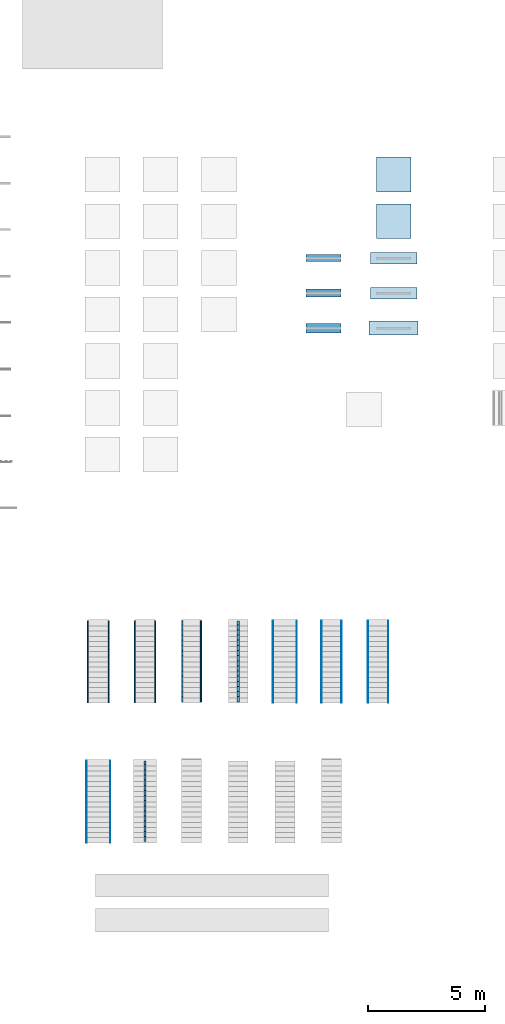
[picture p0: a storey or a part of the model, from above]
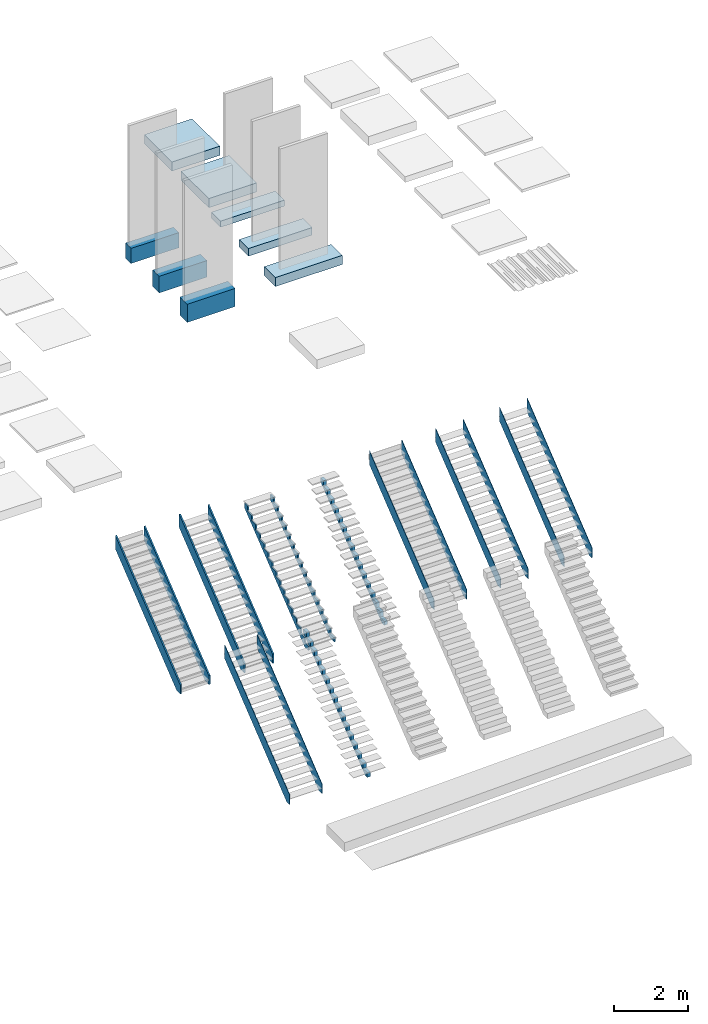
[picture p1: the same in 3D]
Properties of the parts of a building model (IFC2X3), part 3 of 3

# IfcWallStandardCase: Basic Wall:21_WA_hout-wrc-hor_rachel_tengel_iso-sw_180_20-30-10-120, Basic Wall:21_WA_hout-wrc-hor_rachel_tengel_iso-sw_180_20-30-10-120:37447
Type - Analytical Properties - Absorptance: 0.1; Heat Transfer Coefficient (U): 0.274174; Roughness: 1; Thermal mass: 47139.2; Thermal Resistance (R): 3.64732
Type - Construction - Function: Exterior; Width: 180 mm; Wrapping at Inserts: Exterior
Type - Fire Protection - ontvlambaar: no
Type - Graphics - Coarse Scale Fill Color: 8421504; Coarse Scale Fill Pattern: Solid fill
Type - Identity Data - Assembly Code: 2D(21.13); Description: buitenwand, horizontale houten geveldelen, 120mm isolatie steenwol; Keynote: d-21-000; Type Comments: geveldelen op regelwerk: vert 20x30mm op hor 10x30mm; Type Mark: 21-14
Type - Materials and Finishes - Structural Material: 20_isolatie_steenwol
Constraints - Base Constraint: Level: 00_begane grond; Base Extension Distance: 0 mm; Base is Attached: no; Base Offset: 0 mm; Location Line: Core Face: Interior; Related to Mass: no; Room Bounding: yes; Top Extension Distance: 0 mm; Top is Attached: no; Top Offset: 0 mm; Unconnected Height: 2000 mm
Dimensions - Area: 4 m2; Length: 2000 mm; Volume: 0.72 m3
Fire Protection - brandwerend: no
Phasing - Phase Created: Renvooi
Structural - Enable Analytical Model: no; Structural: no; Structural Usage: Non-bearing
Text - drs_wall_type: wall test; ifc_test: wall test
Pset_WallCommon - Reference: 21_WA_hout-wrc-hor_rachel_tengel_iso-sw_180_20-30-10-120; LoadBearing: no; ExtendToStructure: no; IsExternal: yes; ThermalTransmittance: 0.274174 kg/K/s3; Combustible: no; Compartmentation: no

# IfcWallStandardCase: Basic Wall:21_WA_mw-bestaand_100, Basic Wall:21_WA_mw-bestaand_100:31143
In: 00_begane grond
Type - PredefinedType: STANDARD; Material: 00_baksteen_bestaand 100 mm
Type - Analytical Properties - Absorptance: 0.1; Heat Transfer Coefficient (U): 4.1; Roughness: 1; Thermal mass: 120120; Thermal Resistance (R): 0.243902
Type - Construction - Function: Exterior; Width: 100 mm; Wrapping at Inserts: Do not wrap
Type - Fire Protection - ontvlambaar: no
Type - Graphics - Coarse Scale Fill Color: 8421504; Coarse Scale Fill Pattern: Solid fill
Type - Identity Data - Assembly Code: 2D(21.11); Description: bestaande buitenwand, halfsteens metselwerk; Keynote: d-21-001; Type Comments: waalformaat 200x100x50, 10mm voeg; Type Mark: 21-04
Constraints - Base Constraint: Level: 00_begane grond; Base Extension Distance: 0 mm; Base is Attached: no; Base Offset: 0 mm; Location Line: Core Face: Exterior; Related to Mass: no; Room Bounding: yes; Top Extension Distance: 0 mm; Top is Attached: no; Top Offset: 0 mm; Unconnected Height: 2000 mm
Dimensions - Area: 4 m2; Length: 2000 mm; Volume: 0.4 m3
Fire Protection - brandwerend: no
Phasing - Phase Created: Renvooi
Structural - Enable Analytical Model: no; Structural: no; Structural Usage: Non-bearing
Text - drs_wall_type: wall test; ifc_test: wall test
Pset_WallCommon - Reference: 21_WA_mw-bestaand_100; LoadBearing: no; ExtendToStructure: no; IsExternal: yes; ThermalTransmittance: 4.1 kg/K/s3; Combustible: no; Compartmentation: no

# IfcWallStandardCase: Basic Wall:21_WA_mw-bestaand_spouw_mw-bestaand_300_100-100-100, Basic Wall:21_WA_mw-bestaand_spouw_mw-bestaand_300_100-100-100:31145
In: 00_begane grond
Type - PredefinedType: STANDARD; Material: 00_baksteen_bestaand 100 mm, 00_lucht_spouw_muur_geventileerd 100 mm, 00_baksteen_bestaand 100 mm
Type - Analytical Properties - Absorptance: 0.1; Heat Transfer Coefficient (U): 1.98096; Roughness: 1; Thermal mass: 240360; Thermal Resistance (R): 0.504805
Type - Construction - Function: Exterior; Width: 300 mm; Wrapping at Inserts: Both
Type - Fire Protection - ontvlambaar: no
Type - Graphics - Coarse Scale Fill Color: 8421504; Coarse Scale Fill Pattern: Solid fill
Type - Identity Data - Assembly Code: 2B(21.22); Description: bestaande buitenwand, spouwmuur, 100-100-100; Keynote: d-21-001; Type Comments: waalformaat 200x100x50, 10mm voeg; Type Mark: 21-06
Type - Materials and Finishes - Structural Material: 00_baksteen_bestaand
Constraints - Base Constraint: Level: 00_begane grond; Base Extension Distance: 0 mm; Base is Attached: no; Base Offset: 0 mm; Location Line: Core Face: Exterior; Related to Mass: no; Room Bounding: yes; Top Extension Distance: 0 mm; Top is Attached: no; Top Offset: 0 mm; Unconnected Height: 2000 mm
Dimensions - Area: 4 m2; Length: 2000 mm; Volume: 1.2 m3
Fire Protection - brandwerend: no
Phasing - Phase Created: Renvooi
Structural - Enable Analytical Model: yes; Rebar Cover - Exterior Face: Rebar Cover Settings: Rebar Cover 1; Rebar Cover - Interior Face: Rebar Cover Settings: Rebar Cover 1; Rebar Cover - Other Faces: Rebar Cover Settings: Rebar Cover 1; Structural: yes; Structural Usage: Bearing
Text - drs_wall_type: wall test; ifc_test: wall test
Pset_WallCommon - Reference: 21_WA_mw-bestaand_spouw_mw-bestaand_300_100-100-100; LoadBearing: yes; ExtendToStructure: no; IsExternal: yes; ThermalTransmittance: 1.98096 kg/K/s3; Combustible: no; Compartmentation: no

# IfcWallStandardCase: Basic Wall:21_WA_mw_100, Basic Wall:21_WA_mw_100:30883
In: 00_begane grond
Type - PredefinedType: STANDARD; Material: 20_baksteen_wf_210x100x50_10mm_voeg_halfsteens_rood_genuanceerd 100 mm
Type - Analytical Properties - Absorptance: 0.1; Heat Transfer Coefficient (U): 4.1; Roughness: 1; Thermal mass: 120120; Thermal Resistance (R): 0.243902
Type - Construction - Function: Exterior; Width: 100 mm; Wrapping at Inserts: Do not wrap
Type - Fire Protection - ontvlambaar: no
Type - Graphics - Coarse Scale Fill Color: 8421504; Coarse Scale Fill Pattern: Solid fill
Type - Identity Data - Assembly Code: 2D(21.11); Description: buitenwand, halfsteens metselwerk; Keynote: d-21-001; Type Comments: waalformaat 200x100x50, 10mm voeg; Type Mark: 21-07
Constraints - Base Constraint: Level: 00_begane grond; Base Extension Distance: 0 mm; Base is Attached: no; Base Offset: 0 mm; Location Line: Core Face: Exterior; Related to Mass: no; Room Bounding: yes; Top Extension Distance: 0 mm; Top is Attached: no; Top Offset: 0 mm; Unconnected Height: 2000 mm
Dimensions - Area: 4 m2; Length: 2000 mm; Volume: 0.4 m3
Fire Protection - brandwerend: no
Phasing - Phase Created: Renvooi
Structural - Enable Analytical Model: no; Structural: no; Structural Usage: Non-bearing
Text - drs_wall_type: wall test; ifc_test: wall test
Pset_WallCommon - Reference: 21_WA_mw_100; LoadBearing: no; ExtendToStructure: no; IsExternal: yes; ThermalTransmittance: 4.1 kg/K/s3; Combustible: no; Compartmentation: no

# IfcWallStandardCase: Basic Wall:21_WA_mw_210, Basic Wall:21_WA_mw_210:30884
In: 00_begane grond
Type - PredefinedType: STANDARD; Material: 20_baksteen_wf_210x100x50_10mm_voeg_halfsteens_rood_genuanceerd 210 mm
Type - Analytical Properties - Absorptance: 0.1; Heat Transfer Coefficient (U): 1.95238; Roughness: 1; Thermal mass: 252252; Thermal Resistance (R): 0.512195
Type - Construction - Function: Exterior; Width: 210 mm; Wrapping at Inserts: Do not wrap
Type - Fire Protection - ontvlambaar: no
Type - Graphics - Coarse Scale Fill Color: 8421504; Coarse Scale Fill Pattern: Solid fill
Type - Identity Data - Assembly Code: 2B(21.21); Description: buitenwand, steens metselwerk; Keynote: d-21-001; Type Comments: waalformaat 200x100x50, 10mm voeg; Type Mark: 21-08
Type - Materials and Finishes - Structural Material: 20_baksteen_wf_210x100x50_10mm_voeg_halfsteens_rood_genuanceerd
Constraints - Base Constraint: Level: 00_begane grond; Base Extension Distance: 0 mm; Base is Attached: no; Base Offset: 0 mm; Location Line: Core Face: Exterior; Related to Mass: no; Room Bounding: yes; Top Extension Distance: 0 mm; Top is Attached: no; Top Offset: 0 mm; Unconnected Height: 2000 mm
Dimensions - Area: 4 m2; Length: 2000 mm; Volume: 0.84 m3
Fire Protection - brandwerend: no
Phasing - Phase Created: Renvooi
Structural - Enable Analytical Model: yes; Rebar Cover - Exterior Face: Rebar Cover Settings: Rebar Cover 1; Rebar Cover - Interior Face: Rebar Cover Settings: Rebar Cover 1; Rebar Cover - Other Faces: Rebar Cover Settings: Rebar Cover 1; Structural: yes; Structural Usage: Bearing
Text - drs_wall_type: wall test; ifc_test: wall test
Pset_WallCommon - Reference: 21_WA_mw_210; LoadBearing: yes; ExtendToStructure: no; IsExternal: yes; ThermalTransmittance: 1.95238 kg/K/s3; Combustible: no; Compartmentation: no

# IfcWallStandardCase: Basic Wall:21_WA_mw_bestaand_210, Basic Wall:21_WA_mw_bestaand_210:31144
In: 00_begane grond
Type - PredefinedType: STANDARD; Material: 00_baksteen_bestaand 210 mm
Type - Analytical Properties - Absorptance: 0.1; Heat Transfer Coefficient (U): 1.95238; Roughness: 1; Thermal mass: 252252; Thermal Resistance (R): 0.512195
Type - Construction - Function: Exterior; Width: 210 mm; Wrapping at Inserts: Do not wrap
Type - Fire Protection - ontvlambaar: no
Type - Graphics - Coarse Scale Fill Color: 8421504; Coarse Scale Fill Pattern: Solid fill
Type - Identity Data - Assembly Code: 2B(21.21); Description: bestaande buitenwand, steens metselwerk; Keynote: d-21-001; Type Comments: waalformaat 200x100x50, 10mm voeg; Type Mark: 21-05
Type - Materials and Finishes - Structural Material: 00_baksteen_bestaand
Constraints - Base Constraint: Level: 00_begane grond; Base Extension Distance: 0 mm; Base is Attached: no; Base Offset: 0 mm; Location Line: Core Face: Exterior; Related to Mass: no; Room Bounding: yes; Top Extension Distance: 0 mm; Top is Attached: no; Top Offset: 0 mm; Unconnected Height: 2000 mm
Dimensions - Area: 4 m2; Length: 2000 mm; Volume: 0.84 m3
Fire Protection - brandwerend: no
Phasing - Phase Created: Renvooi
Structural - Enable Analytical Model: yes; Rebar Cover - Exterior Face: Rebar Cover Settings: Rebar Cover 1; Rebar Cover - Interior Face: Rebar Cover Settings: Rebar Cover 1; Rebar Cover - Other Faces: Rebar Cover Settings: Rebar Cover 1; Structural: yes; Structural Usage: Bearing
Text - drs_wall_type: wall test; ifc_test: wall test
Pset_WallCommon - Reference: 21_WA_mw_bestaand_210; LoadBearing: yes; ExtendToStructure: no; IsExternal: yes; ThermalTransmittance: 1.95238 kg/K/s3; Combustible: no; Compartmentation: no

# IfcWallStandardCase: Basic Wall:21_WA_mw_spouw_170_100-70, Basic Wall:21_WA_mw_spouw_170_100-70:35351
In: 00_begane grond
Type - PredefinedType: STANDARD; Material: 20_baksteen_wf_210x100x50_10mm_voeg_halfsteens_rood_genuanceerd 100 mm, 00_lucht_spouw_muur_geventileerd 70 mm
Type - Analytical Properties - Absorptance: 0.1; Heat Transfer Coefficient (U): 3.90927; Roughness: 1; Thermal mass: 120204; Thermal Resistance (R): 0.255802
Type - Construction - Function: Exterior; Width: 170 mm; Wrapping at Inserts: Do not wrap
Type - Fire Protection - ontvlambaar: no
Type - Graphics - Coarse Scale Fill Color: 8421504; Coarse Scale Fill Pattern: Solid fill
Type - Identity Data - Assembly Code: 2D(21.12); Description: buitenwand, spouwmuur: 100mm mw, 70mm luchtspouw; Keynote: d-21-001; Type Comments: waalformaat 200x100x50, 10mm voeg; Type Mark: 21-10
Constraints - Base Constraint: Level: 00_begane grond; Base Extension Distance: 0 mm; Base is Attached: no; Base Offset: 0 mm; Location Line: Core Face: Interior; Related to Mass: no; Room Bounding: yes; Top Extension Distance: 0 mm; Top is Attached: no; Top Offset: 0 mm; Unconnected Height: 2000 mm
Dimensions - Area: 4 m2; Length: 2000 mm; Volume: 0.68 m3
Fire Protection - brandwerend: no
Phasing - Phase Created: Renvooi
Structural - Enable Analytical Model: no; Structural: no; Structural Usage: Non-bearing
Text - drs_wall_type: wall test; ifc_test: wall test
Pset_WallCommon - Reference: 21_WA_mw_spouw_170_100-70; LoadBearing: no; ExtendToStructure: no; IsExternal: yes; ThermalTransmittance: 3.90927 kg/K/s3; Combustible: no; Compartmentation: no

# IfcWallStandardCase: Basic Wall:21_WA_mw_spouw_iso-sw_170_100-20-50, Basic Wall:21_WA_mw_spouw_iso-sw_170_100-20-50:35352
In: 00_begane grond
Type - PredefinedType: STANDARD; Material: 20_baksteen_wf_210x100x50_10mm_voeg_halfsteens_rood_genuanceerd 100 mm, 00_lucht_spouw_muur_geventileerd 20 mm, 20_isolatie_steenwol 50 mm
Type - Analytical Properties - Absorptance: 0.1; Heat Transfer Coefficient (U): 0.582109; Roughness: 1; Thermal mass: 127244; Thermal Resistance (R): 1.71789
Type - Construction - Function: Exterior; Width: 170 mm; Wrapping at Inserts: Exterior
Type - Fire Protection - ontvlambaar: no
Type - Graphics - Coarse Scale Fill Color: 8421504; Coarse Scale Fill Pattern: Solid fill
Type - Identity Data - Assembly Code: 2D(21.12); Description: buitenwand, spouwmuur: 100mm mw, 20mm luchtspouw, 50mm isolatie steenwol; Keynote: d-21-001; Type Comments: waalformaat 200x100x50, 10mm voeg; Type Mark: 21-11
Constraints - Base Constraint: Level: 00_begane grond; Base Extension Distance: 0 mm; Base is Attached: no; Base Offset: 0 mm; Location Line: Core Face: Interior; Related to Mass: no; Room Bounding: yes; Top Extension Distance: 0 mm; Top is Attached: no; Top Offset: 0 mm; Unconnected Height: 2000 mm
Dimensions - Area: 4 m2; Length: 2000 mm; Volume: 0.68 m3
Fire Protection - brandwerend: no
Phasing - Phase Created: Renvooi
Structural - Enable Analytical Model: no; Structural: no; Structural Usage: Non-bearing
Text - drs_wall_type: wall test; ifc_test: wall test
Pset_WallCommon - Reference: 21_WA_mw_spouw_iso-sw_170_100-20-50; LoadBearing: no; ExtendToStructure: no; IsExternal: yes; ThermalTransmittance: 0.582109 kg/K/s3; Combustible: no; Compartmentation: no

# IfcWallStandardCase: Basic Wall:21_WA_mw_spouw_iso-sw_200_100-30-70 (2)
In: 00_begane grond
Type - PredefinedType: STANDARD; Material: 20_baksteen_wf_210x100x50_10mm_voeg_halfsteens_rood_genuanceerd 100 mm, 00_lucht_spouw_muur_geventileerd 30 mm, 20_isolatie_steenwol 70 mm
Type - Analytical Properties - Absorptance: 0.1; Heat Transfer Coefficient (U): 0.433308; Roughness: 1; Thermal mass: 130096; Thermal Resistance (R): 2.30783
Type - Construction - Function: Exterior; Width: 200 mm; Wrapping at Inserts: Exterior
Type - Fire Protection - ontvlambaar: no
Type - Graphics - Coarse Scale Fill Color: 8421504; Coarse Scale Fill Pattern: Solid fill
Type - Identity Data - Assembly Code: 2D(21.12); Description: buitenwand, spouwmuur: 100mm mw, 30mm luchtspouw, 70mm isolatie steenwol; Keynote: d-21-001; Type Comments: waalformaat 200x100x50, 10mm voeg; Type Mark: 21-12
Constraints - Base Constraint: Level: 00_begane grond; Base Extension Distance: 0 mm; Base is Attached: no; Base Offset: 0 mm; Location Line: Core Face: Interior; Related to Mass: no; Room Bounding: yes; Top Extension Distance: 0 mm; Top is Attached: no; Top Offset: 0 mm; Unconnected Height: 2000 mm
Dimensions - Area: 4 m2; Length: 2000 mm; Volume: 0.8 m3
Fire Protection - brandwerend: no
Phasing - Phase Created: Renvooi
Structural - Enable Analytical Model: no; Structural: no; Structural Usage: Non-bearing
Text - drs_wall_type: wall test; ifc_test: wall test
Pset_WallCommon - Reference: 21_WA_mw_spouw_iso-sw_200_100-30-70; LoadBearing: no; ExtendToStructure: no; IsExternal: yes; ThermalTransmittance: 0.433308 kg/K/s3; Combustible: no; Compartmentation: no
Name (Basic Wall:21_WA_mw_spouw_iso-sw_200_100-30-70:...)
35353
35357

# IfcWallStandardCase: Basic Wall:21_WA_mw_spouw_mw_300_100-100-100, Basic Wall:21_WA_mw_spouw_mw_300_100-100-100:30885
In: 00_begane grond
Type - PredefinedType: STANDARD; Material: 20_baksteen_wf_210x100x50_10mm_voeg_halfsteens_rood_genuanceerd 100 mm, 00_lucht_spouw_muur_geventileerd 100 mm, 20_baksteen_wf_210x100x50_10mm_voeg_halfsteens_rood_genuanceerd 100 mm
Type - Analytical Properties - Absorptance: 0.1; Heat Transfer Coefficient (U): 1.98096; Roughness: 1; Thermal mass: 240360; Thermal Resistance (R): 0.504805
Type - Construction - Function: Exterior; Width: 300 mm; Wrapping at Inserts: Both
Type - Fire Protection - ontvlambaar: no
Type - Graphics - Coarse Scale Fill Color: 8421504; Coarse Scale Fill Pattern: Solid fill
Type - Identity Data - Assembly Code: 2B(21.22); Description: buitenwand, spouwmuur, 100-100-100; Keynote: d-21-001; Type Comments: waalformaat 200x100x50, 10mm voeg; Type Mark: 21-09
Type - Materials and Finishes - Structural Material: 20_baksteen_wf_210x100x50_10mm_voeg_halfsteens_rood_genuanceerd
Constraints - Base Constraint: Level: 00_begane grond; Base Extension Distance: 0 mm; Base is Attached: no; Base Offset: 0 mm; Location Line: Core Face: Exterior; Related to Mass: no; Room Bounding: yes; Top Extension Distance: 0 mm; Top is Attached: no; Top Offset: 0 mm; Unconnected Height: 2000 mm
Dimensions - Area: 4 m2; Length: 2000 mm; Volume: 1.2 m3
Fire Protection - brandwerend: no
Phasing - Phase Created: Renvooi
Structural - Enable Analytical Model: yes; Rebar Cover - Exterior Face: Rebar Cover Settings: Rebar Cover 1; Rebar Cover - Interior Face: Rebar Cover Settings: Rebar Cover 1; Rebar Cover - Other Faces: Rebar Cover Settings: Rebar Cover 1; Structural: yes; Structural Usage: Bearing
Text - drs_wall_type: wall test; ifc_test: wall test
Pset_WallCommon - Reference: 21_WA_mw_spouw_mw_300_100-100-100; LoadBearing: yes; ExtendToStructure: no; IsExternal: yes; ThermalTransmittance: 1.98096 kg/K/s3; Combustible: no; Compartmentation: no

# IfcWallStandardCase: Basic Wall:21_WA_sandwichpaneel_100x1000, Basic Wall:21_WA_sandwichpaneel_100x1000:50449
In: 00_begane grond
Type - PredefinedType: STANDARD; Material: 41_staal_geanodizeerd_wit 1.6 mm, 20_isolatie_PIR 96.8 mm, 41_staal_geanodizeerd_wit 1.6 mm
Type - Analytical Properties - Absorptance: 0.1; Heat Transfer Coefficient (U): 0.309911; Roughness: 1; Thermal mass: 18460.9; Thermal Resistance (R): 3.22674
Type - Construction - Function: Exterior; Width: 100 mm; Wrapping at Inserts: Exterior
Type - Fire Protection - ontvlambaar: no
Type - Graphics - Coarse Scale Fill Color: 8421504; Coarse Scale Fill Pattern: Solid fill
Type - Identity Data - Assembly Code: 2D(21.13); Description: buitenwand, sandwichpaneel 100mm, PIR isolatie; Keynote: d-21-000; Type Comments: stalen buitenplaat = 0.63mm, stalen binnenplaat = 0.50mm; Type Mark: 21-16
Constraints - Base Constraint: Level: 00_begane grond; Base Extension Distance: 0 mm; Base is Attached: no; Base Offset: 0 mm; Location Line: Core Face: Interior; Related to Mass: no; Room Bounding: yes; Top Extension Distance: 0 mm; Top is Attached: no; Top Offset: 0 mm; Unconnected Height: 2000 mm
Dimensions - Area: 4 m2; Length: 2000 mm; Volume: 0.4 m3
Fire Protection - brandwerend: no
Phasing - Phase Created: Renvooi
Structural - Enable Analytical Model: no; Structural: no; Structural Usage: Non-bearing
Text - drs_wall_type: wall test; ifc_test: wall test
Pset_WallCommon - Reference: 21_WA_sandwichpaneel_100x1000; LoadBearing: no; ExtendToStructure: no; IsExternal: yes; ThermalTransmittance: 0.309911 kg/K/s3; Combustible: no; Compartmentation: no

# IfcWallStandardCase: Basic Wall:21_WA_spouw_iso-sw_140_40-100, Basic Wall:21_WA_spouw_iso-sw_140_40-100:228435
In: 00_begane grond
Type - PredefinedType: STANDARD; Material: 00_lucht_spouw_muur_geventileerd 40 mm, 20_isolatie_steenwol 100 mm
Type - Analytical Properties - Absorptance: 0.1; Heat Transfer Coefficient (U): 0.339216; Roughness: 1; Thermal mass: 14248.2; Thermal Resistance (R): 2.94798
Type - Construction - Function: Exterior; Width: 140 mm; Wrapping at Inserts: Exterior
Type - Fire Protection - ontvlambaar: no
Type - Graphics - Coarse Scale Fill Color: 8421504; Coarse Scale Fill Pattern: Solid fill
Type - Identity Data - Assembly Code: 2E(22.12); Description: 40mm luchtspouw, 100mm isolatie steenwol; Keynote: d-21-001; Type Mark: 21-17
Constraints - Base Constraint: Level: 00_begane grond; Base Extension Distance: 0 mm; Base is Attached: no; Base Offset: 0 mm; Location Line: Core Face: Interior; Related to Mass: no; Room Bounding: yes; Top Extension Distance: 0 mm; Top is Attached: no; Top Offset: 0 mm; Unconnected Height: 2000 mm
Dimensions - Area: 4 m2; Length: 2000 mm; Volume: 0.56 m3
Fire Protection - brandwerend: no
Phasing - Phase Created: Renvooi
Structural - Enable Analytical Model: no; Structural: no; Structural Usage: Non-bearing
Text - drs_wall_type: wall test; ifc_test: wall test
Pset_WallCommon - Reference: 21_WA_spouw_iso-sw_140_40-100; LoadBearing: no; ExtendToStructure: no; IsExternal: yes; ThermalTransmittance: 0.339216 kg/K/s3; Combustible: no; Compartmentation: no

# IfcWallStandardCase: Basic Wall:21_WA_stucwerk_iso-eps_150_30-120, Basic Wall:21_WA_stucwerk_iso-eps_150_30-120:50293
In: 00_begane grond
Type - PredefinedType: STANDARD; Material: 40_stucwerk_exterieur_grof_wit 30 mm, 20_isolatie_EPS 120 mm
Type - Analytical Properties - Absorptance: 0.1; Heat Transfer Coefficient (U): 0.286747; Roughness: 1; Thermal mass: 36313.2; Thermal Resistance (R): 3.48739
Type - Construction - Function: Exterior; Width: 150 mm; Wrapping at Inserts: Exterior
Type - Fire Protection - ontvlambaar: no
Type - Graphics - Coarse Scale Fill Color: 8421504; Coarse Scale Fill Pattern: Solid fill
Type - Identity Data - Assembly Code: 2D(21.10); Description: buitenwand, 30mm stucwerk, 120mm isolatie EPS; Keynote: d-21-000; Type Mark: 21-15
Constraints - Base Constraint: Level: 00_begane grond; Base Extension Distance: 0 mm; Base is Attached: no; Base Offset: 0 mm; Location Line: Core Face: Interior; Related to Mass: no; Room Bounding: yes; Top Extension Distance: 0 mm; Top is Attached: no; Top Offset: 0 mm; Unconnected Height: 2000 mm
Dimensions - Area: 4 m2; Length: 2000 mm; Volume: 0.6 m3
Fire Protection - brandwerend: no
Phasing - Phase Created: Renvooi
Structural - Enable Analytical Model: no; Structural: no; Structural Usage: Non-bearing
Text - drs_wall_type: wall test; ifc_test: wall test
Pset_WallCommon - Reference: 21_WA_stucwerk_iso-eps_150_30-120; LoadBearing: no; ExtendToStructure: no; IsExternal: yes; ThermalTransmittance: 0.286747 kg/K/s3; Combustible: no; Compartmentation: no

# IfcWallStandardCase: Basic Wall:22_WA_cb_G2/400_100, Basic Wall:22_WA_cb_G2/400_100:53177
In: 00_begane grond
Type - PredefinedType: STANDARD; Material: 22_cellenbeton G2/400 100 mm
Type - Analytical Properties - Absorptance: 0.1; Heat Transfer Coefficient (U): 1.2; Roughness: 1; Thermal mass: 40320; Thermal Resistance (R): 0.833333
Type - Construction - Function: Interior; Width: 100 mm; Wrapping at Inserts: Do not wrap
Type - Fire Protection - ontvlambaar: no
Type - Graphics - Coarse Scale Fill Color: 8421504; Coarse Scale Fill Pattern: Solid fill
Type - Identity Data - Assembly Code: 2E(22.11); Description: niet-dragende binnenwand cellenbeton; Keynote: d-22-003; Type Comments: blokken/elementen gelijmd, d =100mm; Type Mark: 22-02
Constraints - Base Constraint: Level: 00_begane grond; Base Extension Distance: 0 mm; Base is Attached: no; Base Offset: 0 mm; Location Line: Core Face: Exterior; Related to Mass: no; Room Bounding: yes; Top Extension Distance: 0 mm; Top is Attached: no; Top Offset: 0 mm; Unconnected Height: 2000 mm
Dimensions - Area: 4 m2; Length: 2000 mm; Volume: 0.4 m3
Fire Protection - brandwerend: no
Phasing - Phase Created: Renvooi
Structural - Enable Analytical Model: no; Structural: no; Structural Usage: Non-bearing
Pset_WallCommon - Reference: 22_WA_cb_G2/400_100; LoadBearing: no; ExtendToStructure: no; IsExternal: no; ThermalTransmittance: 1.2 kg/K/s3; Combustible: no; Compartmentation: no

# IfcWallStandardCase: Basic Wall:22_WA_glazen_bouwsteen_80, Basic Wall:22_WA_glazen_bouwsteen_80:54317
In: 00_begane grond
Type - PredefinedType: STANDARD; Material: 22_glazen_bouwsteen 80 mm
Type - Analytical Properties - Absorptance: 0.1; Heat Transfer Coefficient (U): 2.81125; Roughness: 1; Thermal mass: 62832; Thermal Resistance (R): 0.355714
Type - Construction - Function: Interior; Width: 80 mm; Wrapping at Inserts: Do not wrap
Type - Fire Protection - ontvlambaar: no
Type - Graphics - Coarse Scale Fill Color: 8421504; Coarse Scale Fill Pattern: Solid fill
Type - Identity Data - Assembly Code: 2E(22.10); Description: niet-dragende binnenwand glazen bouwstenen; Keynote: d-22-000; Type Comments: blokken gemetseld, 190x190mm, voeg 10mm, d =80mm; Type Mark: 22-04
Constraints - Base Constraint: Level: 00_begane grond; Base Extension Distance: 0 mm; Base is Attached: no; Base Offset: 0 mm; Location Line: Core Face: Exterior; Related to Mass: no; Room Bounding: yes; Top Extension Distance: 0 mm; Top is Attached: no; Top Offset: 0 mm; Unconnected Height: 2000 mm
Dimensions - Area: 4 m2; Length: 2000 mm; Volume: 0.32 m3
Fire Protection - brandwerend: no
Phasing - Phase Created: Renvooi
Structural - Enable Analytical Model: no; Structural: no; Structural Usage: Non-bearing
Pset_WallCommon - Reference: 22_WA_glazen_bouwsteen_80; LoadBearing: no; ExtendToStructure: no; IsExternal: no; ThermalTransmittance: 2.81125 kg/K/s3; Combustible: no; Compartmentation: no

# IfcWallStandardCase: Basic Wall:22_WA_kzs_CS12_100, Basic Wall:22_WA_kzs_CS12_100:53048
In: 00_begane grond
Type - PredefinedType: STANDARD; Material: 22_kalkzandsteen_CS12 100 mm
Type - Analytical Properties - Absorptance: 0.1; Heat Transfer Coefficient (U): 8.6; Roughness: 1; Thermal mass: 155400; Thermal Resistance (R): 0.116279
Type - Construction - Function: Interior; Width: 100 mm; Wrapping at Inserts: Do not wrap
Type - Fire Protection - ontvlambaar: no
Type - Graphics - Coarse Scale Fill Color: 8421504; Coarse Scale Fill Pattern: Solid fill
Type - Identity Data - Assembly Code: 2E(22.11); Description: niet-dragende binnenwand kalkzandsteen, klasse CS12; Keynote: d-22-051; Type Comments: blokken/elementen gelijmd, d =100mm; Type Mark: 22-01
Constraints - Base Constraint: Level: 00_begane grond; Base Extension Distance: 0 mm; Base is Attached: no; Base Offset: 0 mm; Location Line: Core Face: Exterior; Related to Mass: no; Room Bounding: yes; Top Extension Distance: 0 mm; Top is Attached: no; Top Offset: 0 mm; Unconnected Height: 2000 mm
Dimensions - Area: 4 m2; Length: 2000 mm; Volume: 0.4 m3
Fire Protection - brandwerend: no
Phasing - Phase Created: Renvooi
Structural - Enable Analytical Model: no; Structural: no; Structural Usage: Non-bearing
Pset_WallCommon - Reference: 22_WA_kzs_CS12_100; LoadBearing: no; ExtendToStructure: no; IsExternal: no; ThermalTransmittance: 8.6 kg/K/s3; Combustible: no; Compartmentation: no

# IfcWallStandardCase: Basic Wall:22_WA_ms-wand_gips_isolatie_gips_95_12.5-70-12.5, Basic Wall:22_WA_ms-wand_gips_isolatie_gips_95_12.5-70-12.5:53216
In: 00_begane grond
Type - PredefinedType: STANDARD; Material: 22_gips_beplating_wand_610mm 12.5 mm, 20_isolatie_steenwol 70 mm, 22_gips_beplating_wand_610mm 12.5 mm
Type - Analytical Properties - Absorptance: 0.1; Heat Transfer Coefficient (U): 0.476807; Roughness: 1; Thermal mass: 33040; Thermal Resistance (R): 2.09729
Type - Construction - Function: Interior; Width: 95 mm; Wrapping at Inserts: Do not wrap
Type - Fire Protection - ontvlambaar: no
Type - Graphics - Coarse Scale Fill Color: 8421504; Coarse Scale Fill Pattern: Solid fill
Type - Identity Data - Assembly Code: 2E(22.13); Description: niet-dragende binnenwand metalstud, 70mm isolatie steenwol; Keynote: d-22-000; Type Comments: 12.5mm gipsplaat aan beide zijden; Type Mark: 22-03
Constraints - Base Constraint: Level: 00_begane grond; Base Extension Distance: 0 mm; Base is Attached: no; Base Offset: 0 mm; Location Line: Core Face: Exterior; Related to Mass: no; Room Bounding: yes; Top Extension Distance: 0 mm; Top is Attached: no; Top Offset: 0 mm; Unconnected Height: 2000 mm
Dimensions - Area: 4 m2; Length: 2000 mm; Volume: 0.38 m3
Fire Protection - brandwerend: no
Phasing - Phase Created: Renvooi
Structural - Enable Analytical Model: no; Structural: no; Structural Usage: Non-bearing
Pset_WallCommon - Reference: 22_WA_ms-wand_gips_isolatie_gips_95_12.5-70-12.5; LoadBearing: no; ExtendToStructure: no; IsExternal: no; ThermalTransmittance: 0.476807 kg/K/s3; Combustible: no; Compartmentation: no

# IfcWallStandardCase: Basic Wall:28_WA_cb_G4/600_100, Basic Wall:28_WA_cb_G4/600_100:51594
In: 00_begane grond
Type - PredefinedType: STANDARD; Material: 28_cellenbeton_G4/600 100 mm
Type - Analytical Properties - Absorptance: 0.1; Heat Transfer Coefficient (U): 1.6; Roughness: 1; Thermal mass: 48720; Thermal Resistance (R): 0.625
Type - Construction - Function: Core-shaft; Width: 100 mm; Wrapping at Inserts: Do not wrap
Type - Fire Protection - ontvlambaar: no
Type - Graphics - Coarse Scale Fill Color: 8421504; Coarse Scale Fill Pattern: Solid fill
Type - Identity Data - Assembly Code: 2B(28.21); Description: dragende binnenwand cellenbeton, klasse G4/600; Keynote: d-22-004; Type Comments: blokken/elementen gelijmd, d =100mm; Type Mark: 28-05
Type - Materials and Finishes - Structural Material: 28_cellenbeton_G4/600
Constraints - Base Constraint: Level: 00_begane grond; Base Extension Distance: 0 mm; Base is Attached: no; Base Offset: 0 mm; Location Line: Core Face: Exterior; Related to Mass: no; Room Bounding: yes; Top Extension Distance: 0 mm; Top is Attached: no; Top Offset: 0 mm; Unconnected Height: 2000 mm
Dimensions - Area: 4 m2; Length: 2000 mm; Volume: 0.4 m3
Fire Protection - brandwerend: no
Phasing - Phase Created: Renvooi
Structural - Enable Analytical Model: yes; Rebar Cover - Exterior Face: Rebar Cover Settings: Rebar Cover 1; Rebar Cover - Interior Face: Rebar Cover Settings: Rebar Cover 1; Rebar Cover - Other Faces: Rebar Cover Settings: Rebar Cover 1; Structural: yes; Structural Usage: Bearing
Text - drs_wall_type: wall test; ifc_test: wall test
Pset_WallCommon - Reference: 28_WA_cb_G4/600_100; LoadBearing: yes; ExtendToStructure: no; IsExternal: yes; ThermalTransmittance: 1.6 kg/K/s3; Combustible: no; Compartmentation: no

# IfcWallStandardCase: Basic Wall:28_WA_cb_G4/600_150, Basic Wall:28_WA_cb_G4/600_150:228787
In: 00_begane grond
Type - PredefinedType: STANDARD; Material: 28_cellenbeton_G4/600 150 mm
Type - Analytical Properties - Absorptance: 0.1; Heat Transfer Coefficient (U): 1.06667; Roughness: 1; Thermal mass: 73080; Thermal Resistance (R): 0.9375
Type - Construction - Function: Core-shaft; Width: 150 mm; Wrapping at Inserts: Do not wrap
Type - Fire Protection - ontvlambaar: no
Type - Graphics - Coarse Scale Fill Color: 8421504; Coarse Scale Fill Pattern: Solid fill
Type - Identity Data - Assembly Code: 2B(28.21); Description: dragende binnenwand cellenbeton, klasse G4/600; Keynote: d-22-004; Type Comments: blokken/elementen gelijmd, d =100mm; Type Mark: 28-06
Type - Materials and Finishes - Structural Material: 28_cellenbeton_G4/600
Constraints - Base Constraint: Level: 00_begane grond; Base Extension Distance: 0 mm; Base is Attached: no; Base Offset: 0 mm; Location Line: Core Face: Exterior; Related to Mass: no; Room Bounding: yes; Top Extension Distance: 0 mm; Top is Attached: no; Top Offset: 0 mm; Unconnected Height: 2000 mm
Dimensions - Area: 4 m2; Length: 2000 mm; Volume: 0.6 m3
Fire Protection - brandwerend: no
Phasing - Phase Created: Renvooi
Structural - Enable Analytical Model: yes; Rebar Cover - Exterior Face: Rebar Cover Settings: Rebar Cover 1; Rebar Cover - Interior Face: Rebar Cover Settings: Rebar Cover 1; Rebar Cover - Other Faces: Rebar Cover Settings: Rebar Cover 1; Structural: yes; Structural Usage: Bearing
Text - drs_wall_type: wall test; ifc_test: wall test
Pset_WallCommon - Reference: 28_WA_cb_G4/600_150; LoadBearing: yes; ExtendToStructure: no; IsExternal: yes; ThermalTransmittance: 1.06667 kg/K/s3; Combustible: no; Compartmentation: no

# IfcWallStandardCase: Basic Wall:28_WA_ihwgb_C25_150, Basic Wall:28_WA_ihwgb_C25_150:228590
In: 00_begane grond
Type - PredefinedType: STANDARD; Material: 28_beton_ihwg_C25_30 150 mm
Type - Analytical Properties - Absorptance: 0.1; Heat Transfer Coefficient (U): 6.97333; Roughness: 1; Thermal mass: 226665; Thermal Resistance (R): 0.143403
Type - Construction - Function: Core-shaft; Width: 150 mm; Wrapping at Inserts: Do not wrap
Type - Graphics - Coarse Scale Fill Color: 0
Type - Identity Data - Assembly Code: 2B(28.21); Description: dragende binnenwand beton, klasse C25; Keynote: d-22-004; Type Comments: in het werk gestort , d =150mm; Type Mark: 28-08
Type - Materials and Finishes - Structural Material: 28_beton_ihwg_C25_30
Constraints - Base Constraint: Level: 00_begane grond; Base Extension Distance: 0 mm; Base is Attached: no; Base Offset: 0 mm; Location Line: Core Face: Exterior; Related to Mass: no; Room Bounding: yes; Top Extension Distance: 0 mm; Top is Attached: no; Top Offset: 0 mm; Unconnected Height: 2000 mm
Dimensions - Area: 4 m2; Length: 2000 mm; Volume: 0.6 m3
Fire Protection - brandwerend: no
Phasing - Phase Created: Renvooi
Structural - Enable Analytical Model: yes; Rebar Cover - Exterior Face: Rebar Cover Settings: Rebar Cover 1; Rebar Cover - Interior Face: Rebar Cover Settings: Rebar Cover 1; Rebar Cover - Other Faces: Rebar Cover Settings: Rebar Cover 1; Structural: yes; Structural Usage: Bearing
Text - drs_wall_type: wall test; ifc_test: wall test
Pset_WallCommon - Reference: 28_WA_ihwgb_C25_150; LoadBearing: yes; ExtendToStructure: no; IsExternal: yes; ThermalTransmittance: 6.97333 kg/K/s3; Compartmentation: no

# IfcWallStandardCase: Basic Wall:28_WA_kzs-CS16_spouw_kzs-C16_330_150-30-150, Basic Wall:28_WA_kzs-CS16_spouw_kzs-C16_330_150-30-150:50784
In: 00_begane grond
Type - PredefinedType: STANDARD; Material: 28_kalkzandsteen_CS16 150 mm, 00_lucht_spouw_muur_geventileerd 30 mm, 28_kalkzandsteen_CS16 150 mm
Type - Analytical Properties - Absorptance: 0.1; Heat Transfer Coefficient (U): 2.82536; Roughness: 1; Thermal mass: 466236; Thermal Resistance (R): 0.353937
Type - Construction - Function: Core-shaft; Width: 330 mm; Wrapping at Inserts: Do not wrap
Type - Fire Protection - ontvlambaar: no
Type - Graphics - Coarse Scale Fill Color: 8421504; Coarse Scale Fill Pattern: Solid fill
Type - Identity Data - Assembly Code: 2B(28.21); Description: woningscheidende wand kalkzandsteen, klasse CS16; Keynote: d-22-049; Type Comments: blokken/elementen gelijmd, 2x 150mm, spouw 30mm; Type Mark: 28-03
Type - Materials and Finishes - Structural Material: 28_kalkzandsteen_CS16
Constraints - Base Constraint: Level: 00_begane grond; Base Extension Distance: 0 mm; Base is Attached: no; Base Offset: 0 mm; Location Line: Core Face: Exterior; Related to Mass: no; Room Bounding: yes; Top Extension Distance: 0 mm; Top is Attached: no; Top Offset: 0 mm; Unconnected Height: 2000 mm
Dimensions - Area: 4 m2; Length: 2000 mm; Volume: 1.32 m3
Fire Protection - brandwerend: no
Phasing - Phase Created: Renvooi
Structural - Enable Analytical Model: yes; Rebar Cover - Exterior Face: Rebar Cover Settings: Rebar Cover 1; Rebar Cover - Interior Face: Rebar Cover Settings: Rebar Cover 1; Rebar Cover - Other Faces: Rebar Cover Settings: Rebar Cover 1; Structural: yes; Structural Usage: Bearing
Text - drs_wall_type: wall test; ifc_test: wall test
Pset_WallCommon - Reference: 28_WA_kzs-CS16_spouw_kzs-C16_330_150-30-150; LoadBearing: yes; ExtendToStructure: no; IsExternal: yes; ThermalTransmittance: 2.82536 kg/K/s3; Combustible: no; Compartmentation: no

# IfcWallStandardCase: Basic Wall:28_WA_kzs_CS16_100, Basic Wall:28_WA_kzs_CS16_100:37887
In: 00_begane grond
Type - PredefinedType: STANDARD; Material: 28_kalkzandsteen_CS16 100 mm
Type - Analytical Properties - Absorptance: 0.1; Heat Transfer Coefficient (U): 8.6; Roughness: 1; Thermal mass: 155400; Thermal Resistance (R): 0.116279
Type - Construction - Function: Core-shaft; Width: 100 mm; Wrapping at Inserts: Do not wrap
Type - Fire Protection - ontvlambaar: no
Type - Graphics - Coarse Scale Fill Color: 8421504; Coarse Scale Fill Pattern: Solid fill
Type - Identity Data - Assembly Code: 2B(28.21); Description: dragende binnenwand kalkzandsteen, klasse CS16; Keynote: d-22-051; Type Comments: blokken/elementen gelijmd, d =100mm; Type Mark: 28-01
Type - Materials and Finishes - Structural Material: 28_kalkzandsteen_CS16
Constraints - Base Constraint: Level: 00_begane grond; Base Extension Distance: 0 mm; Base is Attached: no; Base Offset: 0 mm; Location Line: Core Face: Exterior; Related to Mass: no; Room Bounding: yes; Top Extension Distance: 0 mm; Top is Attached: no; Top Offset: 0 mm; Unconnected Height: 2000 mm
Dimensions - Area: 4 m2; Length: 2000 mm; Volume: 0.4 m3
Fire Protection - brandwerend: no
Phasing - Phase Created: Renvooi
Structural - Enable Analytical Model: yes; Rebar Cover - Exterior Face: Rebar Cover Settings: Rebar Cover 1; Rebar Cover - Interior Face: Rebar Cover Settings: Rebar Cover 1; Rebar Cover - Other Faces: Rebar Cover Settings: Rebar Cover 1; Structural: yes; Structural Usage: Bearing
Text - drs_wall_type: wall test; ifc_test: wall test
Pset_WallCommon - Reference: 28_WA_kzs_CS16_100; LoadBearing: yes; ExtendToStructure: no; IsExternal: yes; ThermalTransmittance: 8.6 kg/K/s3; Combustible: no; Compartmentation: no

# IfcWallStandardCase: Basic Wall:28_WA_kzs_CS16_150, Basic Wall:28_WA_kzs_CS16_150:50750
In: 00_begane grond
Type - PredefinedType: STANDARD; Material: 28_kalkzandsteen_CS16 150 mm
Type - Analytical Properties - Absorptance: 0.1; Heat Transfer Coefficient (U): 5.73333; Roughness: 1; Thermal mass: 233100; Thermal Resistance (R): 0.174419
Type - Construction - Function: Core-shaft; Width: 150 mm; Wrapping at Inserts: Do not wrap
Type - Fire Protection - ontvlambaar: no
Type - Graphics - Coarse Scale Fill Color: 8421504; Coarse Scale Fill Pattern: Solid fill
Type - Identity Data - Assembly Code: 2B(28.21); Description: dragende binnenwand kalkzandsteen, klasse CS16; Keynote: d-22-049; Type Comments: gelijmd blokken, d = 150mm; Type Mark: 28-02
Type - Materials and Finishes - Structural Material: 28_kalkzandsteen_CS16
Constraints - Base Constraint: Level: 00_begane grond; Base Extension Distance: 0 mm; Base is Attached: no; Base Offset: 0 mm; Location Line: Core Face: Exterior; Related to Mass: no; Room Bounding: yes; Top Extension Distance: 0 mm; Top is Attached: no; Top Offset: 0 mm; Unconnected Height: 2000 mm
Dimensions - Area: 4 m2; Length: 2000 mm; Volume: 0.6 m3
Fire Protection - brandwerend: no
Phasing - Phase Created: Renvooi
Structural - Enable Analytical Model: yes; Rebar Cover - Exterior Face: Rebar Cover Settings: Rebar Cover 1; Rebar Cover - Interior Face: Rebar Cover Settings: Rebar Cover 1; Rebar Cover - Other Faces: Rebar Cover Settings: Rebar Cover 1; Structural: yes; Structural Usage: Bearing
Text - drs_wall_type: wall test; ifc_test: wall test
Pset_WallCommon - Reference: 28_WA_kzs_CS16_150; LoadBearing: yes; ExtendToStructure: no; IsExternal: yes; ThermalTransmittance: 5.73333 kg/K/s3; Combustible: no; Compartmentation: no

# IfcWallStandardCase: Basic Wall:28_WA_por_PM25_140, Basic Wall:28_WA_por_PM25_140:51261
In: 00_begane grond
Type - PredefinedType: STANDARD; Material: 28_poriso_dragend 140 mm
Type - Analytical Properties - Absorptance: 0.1; Heat Transfer Coefficient (U): 1.92857; Roughness: 1; Thermal mass: 122304; Thermal Resistance (R): 0.518519
Type - Construction - Function: Core-shaft; Width: 140 mm; Wrapping at Inserts: Do not wrap
Type - Fire Protection - ontvlambaar: no
Type - Graphics - Coarse Scale Fill Color: 8421504; Coarse Scale Fill Pattern: Solid fill
Type - Identity Data - Assembly Code: 2B(28.21); Description: dragende binnenwand porotherm; Keynote: d-22-000; Type Comments: blokken/elementen gemetseld =140mm; Type Mark: 28-04
Type - Materials and Finishes - Structural Material: 28_poriso_dragend
Constraints - Base Constraint: Level: 00_begane grond; Base Extension Distance: 0 mm; Base is Attached: no; Base Offset: 0 mm; Location Line: Core Face: Exterior; Related to Mass: no; Room Bounding: yes; Top Extension Distance: 0 mm; Top is Attached: no; Top Offset: 0 mm; Unconnected Height: 2000 mm
Dimensions - Area: 4 m2; Length: 2000 mm; Volume: 0.56 m3
Fire Protection - brandwerend: no
Phasing - Phase Created: Renvooi
Structural - Enable Analytical Model: yes; Rebar Cover - Exterior Face: Rebar Cover Settings: Rebar Cover 1; Rebar Cover - Interior Face: Rebar Cover Settings: Rebar Cover 1; Rebar Cover - Other Faces: Rebar Cover Settings: Rebar Cover 1; Structural: yes; Structural Usage: Bearing
Text - drs_wall_type: wall test; ifc_test: wall test
Pset_WallCommon - Reference: 28_WA_por_PM25_140; LoadBearing: yes; ExtendToStructure: no; IsExternal: yes; ThermalTransmittance: 1.92857 kg/K/s3; Combustible: no; Compartmentation: no

# IfcWallStandardCase: Basic Wall:28_WA_prefabb_C45_150, Basic Wall:28_WA_prefabb_C45_150:52058
In: 00_begane grond
Type - PredefinedType: STANDARD; Material: layer 150 mm
Type - Analytical Properties - Absorptance: 0.1; Heat Transfer Coefficient (U): 6.97333; Roughness: 1; Thermal mass: 226665; Thermal Resistance (R): 0.143403
Type - Construction - Function: Core-shaft; Width: 150 mm; Wrapping at Inserts: Do not wrap
Type - Fire Protection - ontvlambaar: no
Type - Graphics - Coarse Scale Fill Color: 8421504; Coarse Scale Fill Pattern: Solid fill
Type - Identity Data - Assembly Code: 2B(28.21); Description: dragende binnenwand beton, klasse C45; Keynote: d-22-000; Type Comments: geprefabriceerd , d =150mm; Type Mark: 28-07
Constraints - Base Constraint: Level: 00_begane grond; Base Extension Distance: 0 mm; Base is Attached: no; Base Offset: 0 mm; Location Line: Core Face: Exterior; Related to Mass: no; Room Bounding: yes; Top Extension Distance: 0 mm; Top is Attached: no; Top Offset: 0 mm; Unconnected Height: 2000 mm
Dimensions - Area: 4 m2; Length: 2000 mm; Volume: 0.6 m3
Fire Protection - brandwerend: no
Phasing - Phase Created: Renvooi
Structural - Enable Analytical Model: yes; Rebar Cover - Exterior Face: Rebar Cover Settings: Rebar Cover 1; Rebar Cover - Interior Face: Rebar Cover Settings: Rebar Cover 1; Rebar Cover - Other Faces: Rebar Cover Settings: Rebar Cover 1; Structural: yes; Structural Usage: Bearing
Text - drs_wall_type: wall test; ifc_test: wall test
Pset_WallCommon - Reference: 28_WA_prefabb_C45_150; LoadBearing: yes; ExtendToStructure: no; IsExternal: yes; ThermalTransmittance: 6.97333 kg/K/s3; Combustible: no; Compartmentation: no

# IfcWallStandardCase: Basic Wall:42_WA_stucwerk_20 (2)
In: 00_begane grond
Type - PredefinedType: STANDARD; Material: 40_stucwerk_interieur_fijn_wit 20 mm
Type - Analytical Properties - Absorptance: 0.1; Heat Transfer Coefficient (U): 25.5; Roughness: 1; Thermal mass: 21504; Thermal Resistance (R): 0.0392157
Type - Construction - Function: Interior; Width: 20 mm; Wrapping at Inserts: Do not wrap
Type - Fire Protection - ontvlambaar: no
Type - Graphics - Coarse Scale Fill Color: 8421504; Coarse Scale Fill Pattern: Solid fill
Type - Identity Data - Assembly Code: 2E(42.11); Description: stucwerk interieur, fijn, wit; Keynote: d-40-050; Type Comments: d=20mm; Type Mark: 42-01
Constraints - Base Constraint: Level: 00_begane grond; Base Extension Distance: 0 mm; Related to Mass: no; Room Bounding: yes; Top Extension Distance: 0 mm
Dimensions - Length: 2000 mm
Phasing - Phase Created: Renvooi
Structural - Enable Analytical Model: no; Structural: no; Structural Usage: Non-bearing
Pset_WallCommon - Reference: 42_WA_stucwerk_20; LoadBearing: no; ExtendToStructure: no; IsExternal: no; ThermalTransmittance: 25.5 kg/K/s3; Combustible: no
Name (Basic Wall:42_WA_stucwerk_20:...) | Base Offset (mm) | Location Line | Unconnected Height (mm) | Area (m2) | Volume (m3)
59833 | 0 | Core Face: Exterior | 2000 | 4 | 0.08 | Constraints - Base is Attached: no; Top is Attached: no; Top Offset: 0 mm; Fire Protection - brandwerend: no; Pset_WallCommon - Compartmentation: no
60260 | 1500 | Wall Centerline | 500 | 1 | 0.02 | Constraints - Location Line Offset: 0 mm

# IfcWallStandardCase: Basic Wall:42_WA_tegelwerk_150x150x10mm_op cementmortel_wit (2)
In: 00_begane grond
Type - PredefinedType: STANDARD; Material: 40_tegels_keramisch_150x150mm_wit 10 mm, 00_zandcement 20 mm
Type - Analytical Properties - Absorptance: 0.1; Heat Transfer Coefficient (U): 41.84; Roughness: 1; Thermal mass: 55824; Thermal Resistance (R): 0.0239006
Type - Construction - Function: Interior; Width: 30 mm; Wrapping at Inserts: Do not wrap
Type - Fire Protection - ontvlambaar: no
Type - Graphics - Coarse Scale Fill Color: 8421504; Coarse Scale Fill Pattern: Solid fill
Type - Identity Data - Assembly Code: 2E(42.12); Description: tegelwerk 150x150mm, wit, d = 10mm; Keynote: d-40-000; Type Comments: op cementmortel 20mm; Type Mark: 42-02
Constraints - Base Constraint: Level: 00_begane grond; Base Extension Distance: 0 mm; Base Offset: 0 mm; Related to Mass: no; Room Bounding: yes; Top Extension Distance: 0 mm
Dimensions - Length: 2000 mm
Phasing - Phase Created: Renvooi
Structural - Enable Analytical Model: no; Structural: no; Structural Usage: Non-bearing
Pset_WallCommon - Reference: 42_WA_tegelwerk_150x150x10mm_op cementmortel_wit; LoadBearing: no; ExtendToStructure: no; IsExternal: no; ThermalTransmittance: 41.84 kg/K/s3; Combustible: no
Name (Basic Wall:42_WA_tegelwerk_150x150x10mm_op cementmortel_wit:...) | Location Line | Unconnected Height (mm) | Area (m2) | Volume (m3)
59922 | Core Face: Exterior | 2000 | 4 | 0.12 | Constraints - Base is Attached: no; Top is Attached: no; Top Offset: 0 mm; Fire Protection - brandwerend: no; Pset_WallCommon - Compartmentation: no
60259 | Wall Centerline | 1500 | 3 | 0.09 | Constraints - Location Line Offset: 0 mm
